VERSION 5.7 ;
  NOWIREEXTENSIONATPIN ON ;
  DIVIDERCHAR "/" ;
  BUSBITCHARS "[]" ;
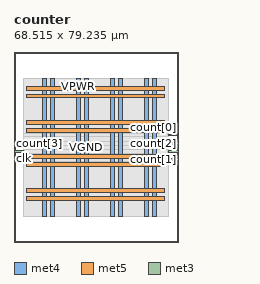
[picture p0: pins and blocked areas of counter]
MACRO counter
  CLASS BLOCK ;
  FOREIGN counter ;
  ORIGIN 0.000 0.000 ;
  SIZE 68.515 BY 79.235 ;
  PIN VGND
    DIRECTION INOUT ;
    USE GROUND ;
    PORT
      LAYER met4 ;
        RECT 15.150 10.640 16.750 68.240 ;
    END
    PORT
      LAYER met4 ;
        RECT 29.410 10.640 31.010 68.240 ;
    END
    PORT
      LAYER met4 ;
        RECT 43.670 10.640 45.270 68.240 ;
    END
    PORT
      LAYER met4 ;
        RECT 57.930 10.640 59.530 68.240 ;
    END
    PORT
      LAYER met5 ;
        RECT 5.280 20.520 62.800 22.120 ;
    END
    PORT
      LAYER met5 ;
        RECT 5.280 34.800 62.800 36.400 ;
    END
    PORT
      LAYER met5 ;
        RECT 5.280 49.080 62.800 50.680 ;
    END
    PORT
      LAYER met5 ;
        RECT 5.280 63.360 62.800 64.960 ;
    END
  END VGND
  PIN VPWR
    DIRECTION INOUT ;
    USE POWER ;
    PORT
      LAYER met4 ;
        RECT 11.850 10.640 13.450 68.240 ;
    END
    PORT
      LAYER met4 ;
        RECT 26.110 10.640 27.710 68.240 ;
    END
    PORT
      LAYER met4 ;
        RECT 40.370 10.640 41.970 68.240 ;
    END
    PORT
      LAYER met4 ;
        RECT 54.630 10.640 56.230 68.240 ;
    END
    PORT
      LAYER met5 ;
        RECT 5.280 17.220 62.800 18.820 ;
    END
    PORT
      LAYER met5 ;
        RECT 5.280 31.500 62.800 33.100 ;
    END
    PORT
      LAYER met5 ;
        RECT 5.280 45.780 62.800 47.380 ;
    END
    PORT
      LAYER met5 ;
        RECT 5.280 60.060 62.800 61.660 ;
    END
  END VPWR
  PIN clk
    DIRECTION INPUT ;
    USE SIGNAL ;
    ANTENNAGATEAREA 0.196500 ;
    PORT
      LAYER met3 ;
        RECT 0.000 37.440 4.000 38.040 ;
    END
  END clk
  PIN count[0]
    DIRECTION OUTPUT TRISTATE ;
    USE SIGNAL ;
    ANTENNADIFFAREA 0.340600 ;
    PORT
      LAYER met3 ;
        RECT 64.515 44.240 68.515 44.840 ;
    END
  END count[0]
  PIN count[1]
    DIRECTION OUTPUT TRISTATE ;
    USE SIGNAL ;
    ANTENNADIFFAREA 0.340600 ;
    PORT
      LAYER met3 ;
        RECT 64.515 34.040 68.515 34.640 ;
    END
  END count[1]
  PIN count[2]
    DIRECTION OUTPUT TRISTATE ;
    USE SIGNAL ;
    ANTENNADIFFAREA 0.340600 ;
    PORT
      LAYER met3 ;
        RECT 64.515 40.840 68.515 41.440 ;
    END
  END count[2]
  PIN count[3]
    DIRECTION OUTPUT TRISTATE ;
    USE SIGNAL ;
    ANTENNADIFFAREA 0.340600 ;
    PORT
      LAYER met3 ;
        RECT 0.000 40.840 4.000 41.440 ;
    END
  END count[3]
  PIN rst
    DIRECTION INPUT ;
    USE SIGNAL ;
    ANTENNAGATEAREA 0.126000 ;
    PORT
      LAYER met3 ;
        RECT 64.515 37.440 68.515 38.040 ;
    END
  END rst
  OBS
      LAYER li1 ;
        RECT 5.520 10.795 62.560 68.085 ;
      LAYER met1 ;
        RECT 5.520 10.640 63.870 68.240 ;
      LAYER met2 ;
        RECT 6.070 10.695 63.850 68.185 ;
      LAYER met3 ;
        RECT 3.990 45.240 64.515 68.165 ;
        RECT 3.990 43.840 64.115 45.240 ;
        RECT 3.990 41.840 64.515 43.840 ;
        RECT 4.400 40.440 64.115 41.840 ;
        RECT 3.990 38.440 64.515 40.440 ;
        RECT 4.400 37.040 64.115 38.440 ;
        RECT 3.990 35.040 64.515 37.040 ;
        RECT 3.990 33.640 64.115 35.040 ;
        RECT 3.990 10.715 64.515 33.640 ;
  END
END counter
END LIBRARY

